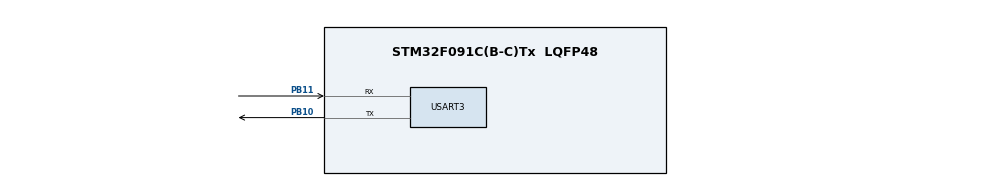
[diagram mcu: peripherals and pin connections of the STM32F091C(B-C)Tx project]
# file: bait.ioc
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Mcu.Family=STM32F0
Mcu.Name=STM32F091C(B-C)Tx
Mcu.Package=LQFP48
PB10.Mode=Asynchronous
PB10.Signal=USART3_TX
PB11.Mode=Asynchronous
PB11.Signal=USART3_RX
ProjectManager.HeapSize=0x200
ProjectManager.StackSize=0x400
ProjectManager.TargetToolchain=Makefile
RCC.AHBFreq_Value=16000000
RCC.APB1Freq_Value=16000000
RCC.APB1TimFreq_Value=16000000
RCC.HCLKFreq_Value=16000000
RCC.PLLDivider=RCC_PREDIV_DIV2
RCC.PLLMUL=RCC_PLL_MUL4
RCC.SYSCLKFreq_VALUE=16000000
RCC.SYSCLKSource=RCC_SYSCLKSOURCE_PLLCLK
USART3.VirtualMode-Asynchronous=VM_ASYNC
board=custom

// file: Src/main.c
/* USER CODE BEGIN Header */
/**
  ******************************************************************************
  * @file           : main.c
  * @brief          : Main program body
  ******************************************************************************
  ** This notice applies to any and all portions of this file
  * that are not between comment pairs USER CODE BEGIN and
  * USER CODE END. Other portions of this file, whether
  * inserted by the user or by software development tools
  * are owned by their respective copyright owners.
  *
  * COPYRIGHT(c) 2019 STMicroelectronics
  *
  * Redistribution and use in source and binary forms, with or without modification,
  * are permitted provided that the following conditions are met:
  *   1. Redistributions of source code must retain the above copyright notice,
  *      this list of conditions and the following disclaimer.
  *   2. Redistributions in binary form must reproduce the above copyright notice,
  *      this list of conditions and the following disclaimer in the documentation
  *      and/or other materials provided with the distribution.
  *   3. Neither the name of STMicroelectronics nor the names of its contributors
  *      may be used to endorse or promote products derived from this software
  *      without specific prior written permission.
  *
  * THIS SOFTWARE IS PROVIDED BY THE COPYRIGHT HOLDERS AND CONTRIBUTORS "AS IS"
  * AND ANY EXPRESS OR IMPLIED WARRANTIES, INCLUDING, BUT NOT LIMITED TO, THE
  * IMPLIED WARRANTIES OF MERCHANTABILITY AND FITNESS FOR A PARTICULAR PURPOSE ARE
  * DISCLAIMED. IN NO EVENT SHALL THE COPYRIGHT HOLDER OR CONTRIBUTORS BE LIABLE
  * FOR ANY DIRECT, INDIRECT, INCIDENTAL, SPECIAL, EXEMPLARY, OR CONSEQUENTIAL
  * DAMAGES (INCLUDING, BUT NOT LIMITED TO, PROCUREMENT OF SUBSTITUTE GOODS OR
  * SERVICES; LOSS OF USE, DATA, OR PROFITS; OR BUSINESS INTERRUPTION) HOWEVER
  * CAUSED AND ON ANY THEORY OF LIABILITY, WHETHER IN CONTRACT, STRICT LIABILITY,
  * OR TORT (INCLUDING NEGLIGENCE OR OTHERWISE) ARISING IN ANY WAY OUT OF THE USE
  * OF THIS SOFTWARE, EVEN IF ADVISED OF THE POSSIBILITY OF SUCH DAMAGE.
  *
  ******************************************************************************
  */
/* USER CODE END Header */

#include "main.h"
#include "usart.h"
#include "gpio.h"

void SystemClock_Config(void);

int main(void)
{

  /* MCU Configuration--------------------------------------------------------*/

  /* Reset of all peripherals, Initializes the Flash interface and the Systick. */
  HAL_Init();

  /* Initialize all configured peripherals */
  MX_GPIO_Init();
  MX_USART3_UART_Init();

  /* Infinite loop */
  while (1)
  {

  }
}

void SystemClock_Config(void)
{
  RCC_OscInitTypeDef RCC_OscInitStruct = {0};
  RCC_ClkInitTypeDef RCC_ClkInitStruct = {0};
  RCC_PeriphCLKInitTypeDef PeriphClkInit = {0};

  /**Initializes the CPU, AHB and APB busses clocks
  */
  RCC_OscInitStruct.OscillatorType = RCC_OSCILLATORTYPE_HSI;
  RCC_OscInitStruct.HSIState = RCC_HSI_ON;
  RCC_OscInitStruct.HSICalibrationValue = RCC_HSICALIBRATION_DEFAULT;
  RCC_OscInitStruct.PLL.PLLState = RCC_PLL_NONE;
  if (HAL_RCC_OscConfig(&RCC_OscInitStruct) != HAL_OK)
  {
    Error_Handler();
  }
  /**Initializes the CPU, AHB and APB busses clocks
  */
  RCC_ClkInitStruct.ClockType = RCC_CLOCKTYPE_HCLK|RCC_CLOCKTYPE_SYSCLK
                              |RCC_CLOCKTYPE_PCLK1;
  RCC_ClkInitStruct.SYSCLKSource = RCC_SYSCLKSOURCE_HSI;
  RCC_ClkInitStruct.AHBCLKDivider = RCC_SYSCLK_DIV1;
  RCC_ClkInitStruct.APB1CLKDivider = RCC_HCLK_DIV1;

  if (HAL_RCC_ClockConfig(&RCC_ClkInitStruct, FLASH_LATENCY_0) != HAL_OK)
  {
    Error_Handler();
  }
  PeriphClkInit.PeriphClockSelection = RCC_PERIPHCLK_USART3;
  PeriphClkInit.Usart3ClockSelection = RCC_USART3CLKSOURCE_PCLK1;
  if (HAL_RCCEx_PeriphCLKConfig(&PeriphClkInit) != HAL_OK)
  {
    Error_Handler();
  }
}

void Error_Handler(void)
{
}

/************************ (C) COPYRIGHT STMicroelectronics *****END OF FILE****/
